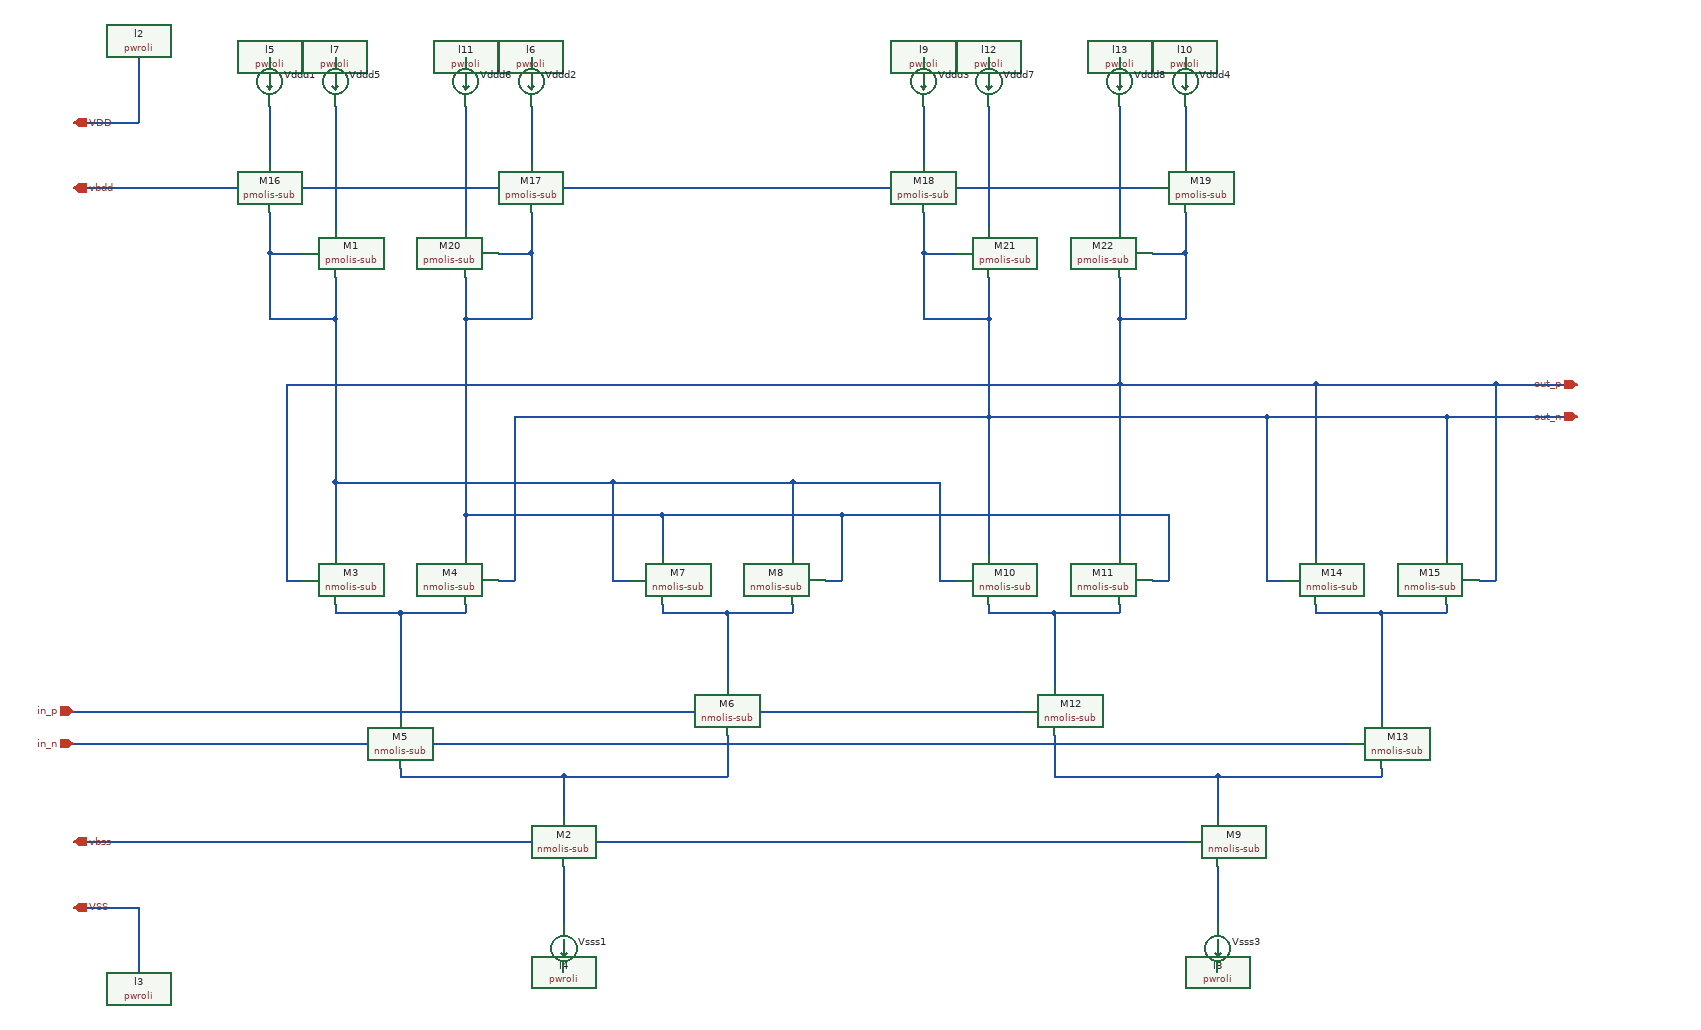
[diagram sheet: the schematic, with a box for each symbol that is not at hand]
v {xschem version=3.4.7RC file_version=1.2
*
* This file is part of XSCHEM,
* a schematic capture and Spice/Vhdl/Verilog netlisting tool for circuit
* simulation.
* Copyright (C) 1998-2023 Stefan Frederik Schippers
*
* This program is free software; you can redistribute it and/or modify
* it under the terms of the GNU General Public License as published by
* the Free Software Foundation; either version 2 of the License, or
* (at your option) any later version.
*
* This program is distributed in the hope that it will be useful,
* but WITHOUT ANY WARRANTY; without even the implied warranty of
* MERCHANTABILITY or FITNESS FOR A PARTICULAR PURPOSE.  See the
* GNU General Public License for more details.
*
* You should have received a copy of the GNU General Public License
* along with this program; if not, write to the Free Software
* Foundation, Inc., 51 Franklin Street, Fifth Floor, Boston, MA 02110-1301 USA
}
G {}
K {}
V {}
S {}
E {}
N 1200 -600 1280 -600 {lab=#net1}
N 1120 -600 1200 -600 {lab=#net1}
N 1120 -610 1120 -600 {lab=#net1}
N 1280 -610 1280 -600 {lab=#net1}
N 800 -600 880 -600 {lab=#net2}
N 800 -600 800 -470 {lab=#net2}
N 720 -600 800 -600 {lab=#net2}
N 720 -610 720 -600 {lab=#net2}
N 880 -610 880 -600 {lab=#net2}
N 720 -760 720 -670 {lab=#net3}
N 880 -720 880 -670 {lab=#net4}
N 1280 -760 1280 -670 {lab=#net3}
N 880 -720 1120 -720 {lab=#net4}
N 880 -960 880 -720 {lab=#net4}
N 1120 -720 1120 -670 {lab=#net4}
N 1060 -640 1080 -640 {lab=#net3}
N 1060 -760 1060 -640 {lab=#net3}
N 720 -760 1060 -760 {lab=#net3}
N 1120 -720 1340 -720 {lab=#net4}
N 1340 -720 1340 -640 {lab=#net4}
N 1320 -640 1340 -640 {lab=#net4}
N 640 -1220 640 -1150 {lab=VDD}
N 960 -1220 960 -1150 {lab=VDD}
N 2000 -600 2080 -600 {lab=#net5}
N 1920 -600 2000 -600 {lab=#net5}
N 1920 -610 1920 -600 {lab=#net5}
N 2080 -610 2080 -600 {lab=#net5}
N 1600 -600 1680 -600 {lab=#net6}
N 1600 -600 1600 -510 {lab=#net6}
N 1520 -600 1600 -600 {lab=#net6}
N 1520 -610 1520 -600 {lab=#net6}
N 1680 -610 1680 -600 {lab=#net6}
N 1520 -840 1520 -670 {lab=out_n}
N 1680 -880 1680 -670 {lab=out_p}
N 1860 -840 2080 -840 {lab=out_n}
N 2080 -840 2080 -670 {lab=out_n}
N 1920 -880 1920 -670 {lab=out_p}
N 1860 -640 1880 -640 {lab=out_n}
N 1860 -840 1860 -640 {lab=out_n}
N 1920 -880 2140 -880 {lab=out_p}
N 2140 -880 2140 -640 {lab=out_p}
N 2120 -640 2140 -640 {lab=out_p}
N 1720 -640 1740 -640 {lab=#net4}
N 1060 -760 1280 -760 {lab=#net3}
N 660 -640 680 -640 {lab=out_p}
N 920 -640 940 -640 {lab=out_n}
N 1680 -880 1920 -880 {lab=out_p}
N 1340 -720 1740 -720 {lab=#net4}
N 1740 -720 1740 -640 {lab=#net4}
N 1280 -760 1460 -760 {lab=#net3}
N 1460 -760 1460 -640 {lab=#net3}
N 1460 -640 1480 -640 {lab=#net3}
N 660 -880 1680 -880 {lab=out_p}
N 660 -880 660 -640 {lab=out_p}
N 940 -840 940 -640 {lab=out_n}
N 1520 -840 1860 -840 {lab=out_n}
N 940 -840 1520 -840 {lab=out_n}
N 2140 -880 2240 -880 {lab=out_p}
N 2080 -840 2240 -840 {lab=out_n}
N 1000 -400 1200 -400 {lab=#net7}
N 1000 -400 1000 -350 {lab=#net7}
N 800 -400 1000 -400 {lab=#net7}
N 1800 -400 1800 -350 {lab=#net8}
N 1600 -400 1800 -400 {lab=#net8}
N 1000 -290 1000 -220 {lab=VSS}
N 1800 -290 1800 -220 {lab=VSS}
N 800 -410 800 -400 {lab=#net7}
N 1200 -450 1200 -400 {lab=#net7}
N 1600 -450 1600 -400 {lab=#net8}
N 2000 -410 2000 -400 {lab=#net8}
N 400 -320 1760 -320 {lab=vbss}
N 400 -480 1560 -480 {lab=in_p}
N 400 -1200 480 -1200 {
lab=VDD}
N 480 -1280 480 -1200 {
lab=VDD}
N 400 -240 480 -240 {
lab=VSS}
N 480 -240 480 -160 {
lab=VSS}
N 720 -1220 720 -1070 {lab=VDD}
N 640 -1040 640 -960 {lab=#net3}
N 640 -960 720 -960 {lab=#net3}
N 720 -1010 720 -960 {lab=#net3}
N 880 -1220 880 -1070 {lab=VDD}
N 880 -1010 880 -960 {lab=#net4}
N 880 -960 960 -960 {lab=#net4}
N 960 -1040 960 -960 {lab=#net4}
N 1440 -1220 1440 -1150 {lab=VDD}
N 1760 -1220 1760 -1150 {lab=VDD}
N 1520 -1220 1520 -1070 {lab=VDD}
N 1440 -1040 1440 -960 {lab=out_n}
N 1440 -960 1520 -960 {lab=out_n}
N 1520 -1010 1520 -960 {lab=out_n}
N 1680 -1220 1680 -1070 {lab=VDD}
N 1680 -1010 1680 -960 {lab=out_p}
N 1680 -960 1760 -960 {lab=out_p}
N 1760 -1040 1760 -960 {lab=out_p}
N 400 -1120 1720 -1120 {lab=vbdd}
N 1520 -960 1520 -840 {lab=out_n}
N 1680 -960 1680 -880 {lab=out_p}
N 1440 -1040 1480 -1040 {lab=out_n}
N 1440 -1090 1440 -1040 {lab=out_n}
N 1720 -1040 1760 -1040 {lab=out_p}
N 1760 -1090 1760 -1040 {lab=out_p}
N 920 -1040 960 -1040 {lab=#net4}
N 960 -1090 960 -1040 {lab=#net4}
N 640 -1040 680 -1040 {lab=#net3}
N 640 -1090 640 -1040 {lab=#net3}
N 720 -960 720 -760 {lab=#net3}
N 1800 -400 2000 -400 {lab=#net8}
N 2000 -600 2000 -470 {lab=#net5}
N 400 -440 1960 -440 {lab=in_n}
N 1200 -600 1200 -510 {lab=#net1}
C {title.sym} 160 -30 0 0 {name=l1 author="om"  net_name=true}
C {pwroli.sym} 1000 -160 0 0 {name=l4 lab=VSS}
C {ammeter.sym} 1000 -190 0 0 {name=Vsss1 
savecurrent=true
lvs_ignore=short}
C {pwroli.sym} 640 -1280 2 0 {name=l5 lab=VDD
}
C {pwroli.sym} 960 -1280 2 0 {name=l6 lab=VDD
}
C {ammeter.sym} 640 -1250 0 0 {name=Vddd1
savecurrent=true
lvs_ignore=short}
C {ammeter.sym} 960 -1250 0 0 {name=Vddd2
savecurrent=true
lvs_ignore=short}
C {pwroli.sym} 1800 -160 0 0 {name=l8 lab=VSS}
C {ammeter.sym} 1800 -190 0 0 {name=Vsss3 
savecurrent=true
lvs_ignore=short}
C {ngspice_probe.sym} 1800 -400 0 0 {name=r7}
C {ngspice_probe.sym} 1000 -400 0 0 {name=r9}
C {ngspice_probe.sym} 840 -600 0 0 {name=r11}
C {ngspice_probe.sym} 1220 -600 0 0 {name=r12}
C {ngspice_probe.sym} 1630 -600 0 0 {name=r14}
C {ngspice_probe.sym} 2030 -600 0 0 {name=r15}
C {ngspice_probe.sym} 2020 -880 0 0 {name=r16}
C {ngspice_probe.sym} 2020 -840 0 0 {name=r17}
C {nmolis-sub.sym} 980 -320 0 0 {name=M2
l=nl
w=nw
ng=1
m=1
substrate=VSS
model=sg13_lv_nmos
spiceprefix=X
}
C {nmolis-sub.sym} 700 -640 0 0 {name=M3
l=nl
w=nw
ng=1
m=1
substrate=VSS
model=sg13_lv_nmos
spiceprefix=X
}
C {nmolis-sub.sym} 900 -640 0 1 {name=M4
l=nl
w=nw
ng=1
m=1
substrate=VSS
model=sg13_lv_nmos
spiceprefix=X
}
C {nmolis-sub.sym} 780 -440 0 0 {name=M5
l=nl
w=nw
ng=1
m=1
substrate=VSS
model=sg13_lv_nmos
spiceprefix=X
}
C {nmolis-sub.sym} 1180 -480 0 0 {name=M6
l=nl
w=nw
ng=1
m=1
substrate=VSS
model=sg13_lv_nmos
spiceprefix=X
}
C {nmolis-sub.sym} 1100 -640 0 0 {name=M7
l=nl
w=nw
ng=1
m=1
substrate=VSS
model=sg13_lv_nmos
spiceprefix=X
}
C {nmolis-sub.sym} 1300 -640 0 1 {name=M8
l=nl
w=nw
ng=1
m=1
substrate=VSS
model=sg13_lv_nmos
spiceprefix=X
}
C {nmolis-sub.sym} 1780 -320 0 0 {name=M9
l=nl
w=nw
ng=1
m=1
substrate=VSS
model=sg13_lv_nmos
spiceprefix=X
}
C {nmolis-sub.sym} 1500 -640 0 0 {name=M10
l=nl
w=nw
ng=1
m=1
substrate=VSS
model=sg13_lv_nmos
spiceprefix=X
}
C {nmolis-sub.sym} 1700 -640 0 1 {name=M11
l=nl
w=nw
ng=1
m=1
substrate=VSS
model=sg13_lv_nmos
spiceprefix=X
}
C {nmolis-sub.sym} 1580 -480 0 0 {name=M12
l=nl
w=nw
ng=1
m=1
substrate=VSS
model=sg13_lv_nmos
spiceprefix=X
}
C {nmolis-sub.sym} 1980 -440 0 0 {name=M13
l=nl
w=nw
ng=1
m=1
substrate=VSS
model=sg13_lv_nmos
spiceprefix=X
}
C {nmolis-sub.sym} 1900 -640 0 0 {name=M14
l=nl
w=nw
ng=1
m=1
substrate=VSS
model=sg13_lv_nmos
spiceprefix=X
}
C {nmolis-sub.sym} 2100 -640 0 1 {name=M15
l=nl
w=nw
ng=1
m=1
substrate=VSS
model=sg13_lv_nmos
spiceprefix=X
}
C {pmolis-sub.sym} 620 -1120 0 0 {name=M16
l=pl
w=150n
ng=1
m=1
substrate=VDD
model=sg13_lv_pmos
spiceprefix=X
}
C {pmolis-sub.sym} 940 -1120 0 0 {name=M17
l=pl
w=150n
ng=1
m=1
substrate=VDD
model=sg13_lv_pmos
spiceprefix=X
}
C {ipin.sym} 400 -480 0 0 {name=p3 lab=in_p
}
C {ipin.sym} 400 -440 0 0 {name=p1 lab=in_n
}
C {opin.sym} 2240 -880 2 1 {name=p5 lab=out_p

}
C {opin.sym} 2240 -840 2 1 {name=p2 lab=out_n

}
C {iopin.sym} 400 -1120 0 1 {name=p13 lab=vbdd}
C {iopin.sym} 400 -320 0 1 {name=p4 lab=vbss}
C {iopin.sym} 400 -1200 0 1 {name=p9 lab=VDD}
C {pwroli.sym} 480 -1280 2 0 {name=l2 lab=VDD
}
C {iopin.sym} 400 -240 0 1 {name=p8 lab=VSS

}
C {pwroli.sym} 480 -160 0 0 {name=l3 lab=VSS}
C {launcher.sym} 220 -800 0 0 {name=h1
descr="write LVS netlist"
tclcommand="
	xschem set netlist_type spice
	set lvs_ignore 1
	set lvs_netlist 1
	set spiceprefix 0
	set last_local_netlist_dir $local_netlist_dir
	set local_netlist_dir 0
	xschem netlist [xschem get current_name].cdl
	set local_netlist_dir $last_local_netlist_dir

"
}
C {launcher.sym} 220 -760 0 0 {name=h2
descr="load OP from TOP"
tclcommand="
	xschem annotate_op $\{netlist_dir\}/[file rootname [file tail [xschem get schname 0]]].raw 0;
	xschem load_raw $\{netlist_dir\}/[file rootname [file tail [xschem get schname 0]]]_dc.raw 0;

"
}
C {pwroli.sym} 720 -1280 2 1 {name=l7 lab=VDD
}
C {ammeter.sym} 720 -1250 0 0 {name=Vddd5
savecurrent=true
lvs_ignore=short}
C {pmolis-sub.sym} 700 -1040 0 0 {name=M1
l=pl
w=0.3u
ng=1
m=1
substrate=VDD
model=sg13_lv_pmos
spiceprefix=X
}
C {pwroli.sym} 880 -1280 2 0 {name=l11 lab=VDD
}
C {ammeter.sym} 880 -1250 0 0 {name=Vddd6
savecurrent=true
lvs_ignore=short}
C {pmolis-sub.sym} 900 -1040 0 1 {name=M20
l=pl
w=0.3u
ng=1
m=1
substrate=VDD
model=sg13_lv_pmos
spiceprefix=X
}
C {pwroli.sym} 1440 -1280 2 0 {name=l9 lab=VDD
}
C {pwroli.sym} 1760 -1280 2 0 {name=l10 lab=VDD
}
C {ammeter.sym} 1440 -1250 0 0 {name=Vddd3
savecurrent=true
lvs_ignore=short}
C {ammeter.sym} 1760 -1250 0 0 {name=Vddd4
savecurrent=true
lvs_ignore=short}
C {pmolis-sub.sym} 1420 -1120 0 0 {name=M18
l=pl
w=150n
ng=1
m=1
substrate=VDD
model=sg13_lv_pmos
spiceprefix=X
}
C {pmolis-sub.sym} 1740 -1120 0 0 {name=M19
l=pl
w=150n
ng=1
m=1
substrate=VDD
model=sg13_lv_pmos
spiceprefix=X
}
C {pwroli.sym} 1520 -1280 2 1 {name=l12 lab=VDD
}
C {ammeter.sym} 1520 -1250 0 0 {name=Vddd7
savecurrent=true
lvs_ignore=short}
C {pmolis-sub.sym} 1500 -1040 0 0 {name=M21
l=pl
w=0.3u
ng=1
m=1
substrate=VDD
model=sg13_lv_pmos
spiceprefix=X
}
C {pwroli.sym} 1680 -1280 2 0 {name=l13 lab=VDD
}
C {ammeter.sym} 1680 -1250 0 0 {name=Vddd8
savecurrent=true
lvs_ignore=short}
C {pmolis-sub.sym} 1700 -1040 0 1 {name=M22
l=pl
w=0.3u
ng=1
m=1
substrate=VDD
model=sg13_lv_pmos
spiceprefix=X
}
C {ngspice_probe.sym} 720 -690 0 0 {name=r1}
C {ngspice_probe.sym} 880 -690 0 0 {name=r2}
C {ngspice_probe.sym} 940 -690 0 0 {name=r3}
C {ngspice_probe.sym} 660 -690 0 0 {name=r4}
C {ngspice_probe.sym} 1520 -690 0 0 {name=r5}
C {ngspice_probe.sym} 1680 -690 0 0 {name=r6}
C {ngspice_probe.sym} 1740 -690 0 0 {name=r8}
C {ngspice_probe.sym} 1460 -690 0 0 {name=r10}
